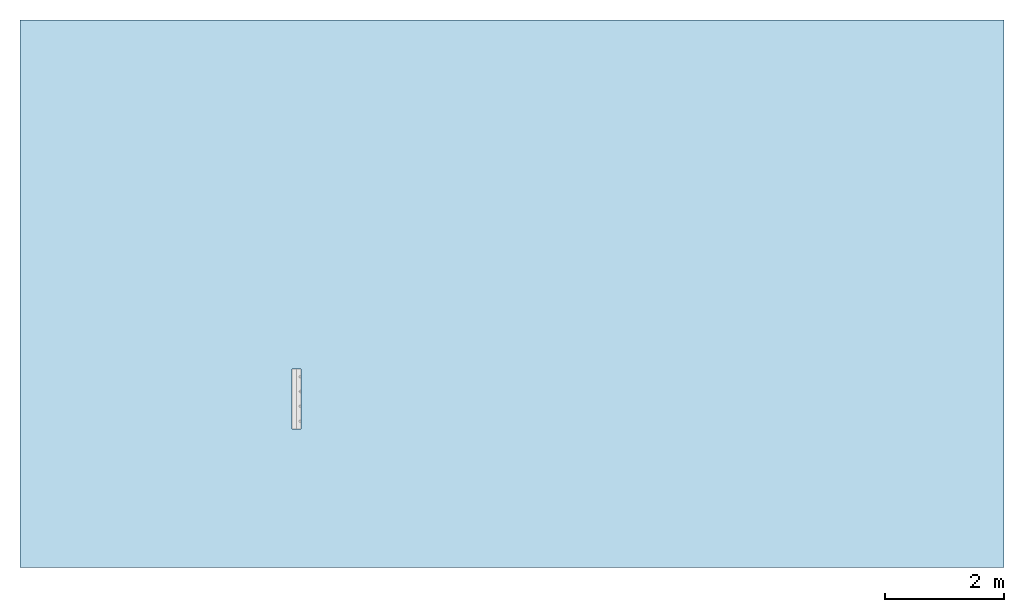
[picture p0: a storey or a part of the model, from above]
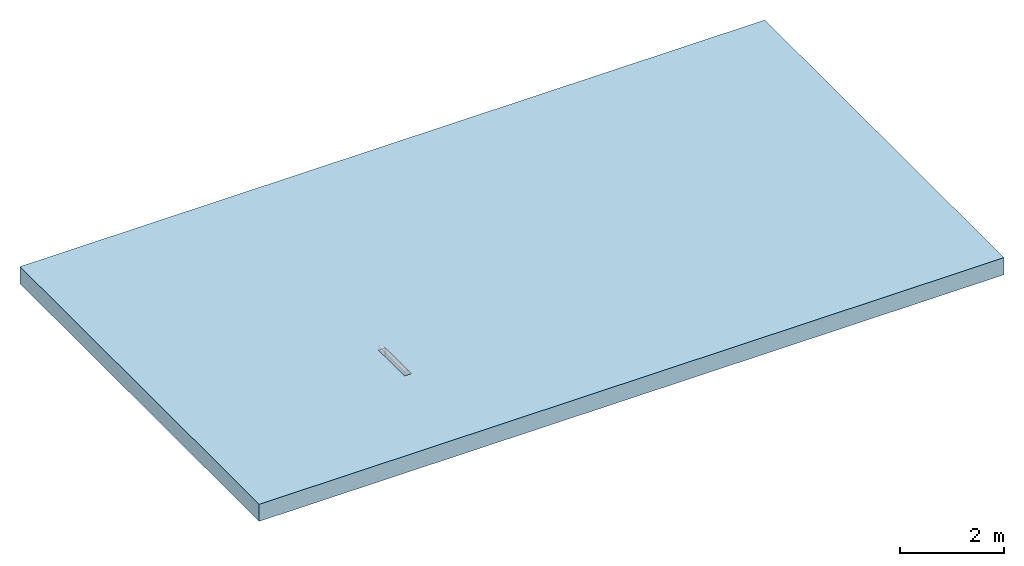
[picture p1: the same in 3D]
Properties of the parts of a building model (IFC2X3)

# File
Description: ViewDefinition [CoordinationView]
File name: 4241 - KDSP380 Channel -1000mm LG.ifc
Time: 2013-09-02T12:16:57
Written by: Autodesk Revit 2013
Made in: 20120221_2030(x64)

# IfcProject, Project Number
LongName: Project Name; Phase: Project Status

# IfcSite, Default
RefLatitude: 42, 21, 30, 344238; RefLongitude: -71, -3, -35, -194702; RefElevation: 0 mm

# IfcBuilding
Pset_BuildingCommon - NumberOfStoreys: 1
Other - Project Name: Project Name; Project Address: ## Street City, State Zip; Project Number: Project Number; Project Status: Project Status; Project Issue Date: Issue Date; Client Name: Owner

# IfcBuildingStorey, Level 1
LongName: Level 1; Elevation: 0 mm
Constraints - Elevation Base: 0; Elevation: 0 mm
Graphics - Symbol: M_Level Head - Circle: M_Level Head - Circle; Symbol at End 1 Default: no; Color: 0; Line Pattern: Center; Symbol at End 2 Default: yes; Line Weight: 1
Identity Data - Structural: no; Name: Level 1; Building Story: yes
Dimensions - Computation Height: 0 mm

# IfcBuildingElementProxy: 4241 - KDSP380 Channel -1000mm LG, Civil-Drainage-Channel-ACO-KerbDrain-SP380:4241 - KDSP380 Channel -1000mm LG:4241 - KDSP380 Channel -1000mm LG:308659
In: Level 1
Material: ACO Polymer Concrete.
Phasing - Phase Created: New Construction
Constraints - Level: Level: Level 1; Moves With Nearby Elements: no
Dimensions - Volume: 28254709 mm3; Endcap void: 205 mm; Void Depth: -280 mm; Void Length: 1000 mm; Access hole: 2 mm; AccessDepth: 2000 mm; Void Width: 150 mm
Pset_BuildingElementProxyCommon - Reference: 4241 - KDSP380 Channel -1000mm LG
Identity Data - Product Code: 4241; Product Page URL: http://www.aco.co.uk/product_detail.php?id=3; Product brochure: http://www.aco.co.uk/download.php?id=120; OmniClass Title: Rainwater Removal; Installation guidelines: http://www.aco.co.uk/download.php?id=120; Manufacturer: ACO Technologies plc - ACO Water Management Division; Cost: 0; OmniClass Number: 23.70.50.24; e-mail Technical: technical@aco.co.uk; Price: POA - contact ACO; e-mail Sales: customersupport@aco.co.uk; Fax: +44 (0)1462 815895; Assembly Code: D2040; Model Description: Combined kerb and drainage system; Telephone: +44 (0)1462 816666; Assembly Description: Rain Water Drainage; Address: ACO Business Park, Hitchin Road, Shefford, Bedfordshire, United Kingdom SG17 5TE; Model: ACO KerbDrain SP380; Maintenance guidelines: http://www.aco.co.uk/download.php?id=120; Type Comments: ACO KerbDrain SP380 splayed kerb unit 1000mm long; URL: www.aco.co.uk
General - TagNumber: 0.000000; SerialNumber: 0.000000
Construction - RH drop kerb: no; Centre Stone: no; RH inlet/outlet end cap: no; RH transition unit: no; SP380 - 1000: yes; Closing end cap: no; LH drop kerb: no; SP380-500: no; LH inlet/outlet end cap: no; LH transition unit: no; Access Unit: no
Materials and Finishes - Channel Colour: Grey; Connection Pipe Material Colour: N/A; Access Cover/Frame Finish: N/A; Access Cover/Frame Colour: N/A; Access Cover/Frame Material: N/A; End Cap Material: N/A; End Cap Colour: N/A; Connection Pipe Material: N/A; Channel Material: Vienite® Synthetic Resin Concrete
Data - Connection Pipe O.D: N/A; Drainage Slot Intake area: 14592mm²/m; Product Weight: 59.6 Kg; Concrete Surround Volume - Load Class A 15 - D 400 - Concrete Pavement: 0.17m³/m; Concrete Surround Volume - Load Class A 15 - D 400 - Grass or Asphalt Pavement: 0.15m³/m; Drainage Slot Width: 50mm; ACO Hydraulic Design Software: http://www.acodesign.co.uk; Invert Depth: 355mm; Product Dimensions: 1000mm x 150mm x 380mm (LxWxH); Installation - Concrete Grade: Refer to brochure; Hydraulic Performance: http://www.aco.co.uk/download.php?id=120; Load Class: A 15 - D 400 A 15 - D 400; Product Standard: BS EN 1433:2002, CE marked, Kitemarked; Channel C.S.A: 0.03m²
Other - CreatedBy: www.aco.co.uk; Revision: 1
Green Building Properties - Channel Recycled Material Content: 20% minimum; End Cap Recyclable: N/A; Channel Recyclable: Fully recyclable; End Cap Recycled Material Content: N/A; Access Cover/Frame Recycled Material Content: N/A; Access Cover/Frame Recyclable: N/A

# IfcOpeningElement: Recess (2)
In: Level 1
Constraints - Level: Level: Level 1; Height Offset From Level: 0 mm; Room Bounding: yes; Related to Mass: no
Dimensions - Perimeter: 51360 mm; Volume: 60546000000 mm3; Area: 151470000 mm2; Thickness: 400 mm
Structural - Enable Analytical Model: no; Structural: no
Phasing - Phase Created: New Construction
Analytical Properties - Roughness: 1; Absorptance: 0.1
Graphics - Coarse Scale Fill Color: 0
Construction - Default Thickness: 400 mm; Function: 0
Materials and Finishes - Structural Material: Plant

# IfcSlab: Floor:Generic Floor - 400mm, Floor:Generic Floor - 400mm:193825
In: Level 1
PredefinedType: FLOOR; Material: Plant 400 mm
Constraints - Level: Level: Level 1; Height Offset From Level: 0 mm; Room Bounding: yes; Related to Mass: no
Dimensions - Perimeter: 51360 mm; Volume: 60546000000 mm3; Area: 151470000 mm2; Thickness: 400 mm
Structural - Enable Analytical Model: no; Structural: no
Phasing - Phase Created: New Construction
Pset_SlabCommon - Reference: Generic Floor - 400mm; IsExternal: no; LoadBearing: yes
Analytical Properties - Roughness: 1; Absorptance: 0.1
Graphics - Coarse Scale Fill Color: 0
Construction - Default Thickness: 400 mm; Function: 0
Materials and Finishes - Structural Material: Plant
